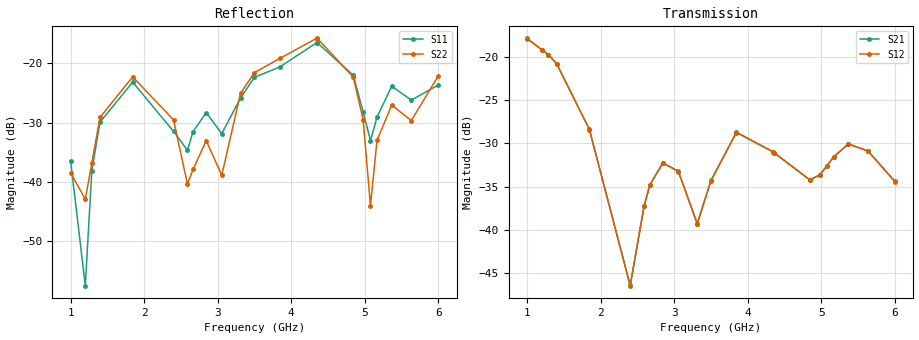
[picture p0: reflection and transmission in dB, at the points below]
!Agilent Technologies,E8364B,MY43040528,A.07.50.67
!Agilent E8364B: A.07.50.67
!Date: Sunday, March 01, 2026 16:23:47
!Correction: S11(Full 2 Port(1,2))
!S21(Full 2 Port(1,2))
!S12(Full 2 Port(1,2))
!S22(Full 2 Port(1,2))
!S2P File: Measurements: S11, S21, S12, S22:
# Hz S  dB  R 50
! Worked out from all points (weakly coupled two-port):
!   451 points, 1 GHz to 6 GHz, reference 50 ohm
!   highest |S21| = -17.88 dB at 1 GHz (marker M1); lowest = -46.4 dB at 2.4 GHz (marker M2)
!   lowest |S11| = -57.5 dB at 1.2 GHz (marker M3), VSWR 1.00, Z = 50 - j0.125 ohm
!   |S11| at or under -10 dB: start of sweep to end of sweep
!   |S22| runs from -44.0 to -15.7 dB; largest |S21 - S12| = 0.00055
!   S11 on the Smith chart (normalised r, x): 1 GHz: 1.03, +0.01; 4.356 GHz: 1.20, -0.26; 6 GHz: 0.97, -0.13
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1e9  -36.43 24.8  -17.88 27.6  -17.92 27.7  -38.46 -7.3
1.2e9  -57.52 -69.8  -19.19 -32.7  -19.23 -32.7  -42.92 77.2
1.288889e9  -38.14 -149.9  -19.75 -61.7  -19.78 -61.6  -36.85 111.4
1.4e9  -29.92 -177.1  -20.80 -99.1  -20.84 -99.0  -29.11 99.5
1.844444e9  -23.16 87.6  -28.38 119.6  -28.41 119.7  -22.27 -8.3
2.4e9  -31.46 23.9  -46.42 -118.5  -46.45 -118.4  -29.52 -113.3
2.588889e9  -34.64 71.3  -37.24 97.6  -37.27 97.7  -40.34 -101.1
2.666667e9  -31.50 77.1  -34.81 62.8  -34.84 62.8  -37.86 -63.2
2.844444e9  -28.31 56.1  -32.25 -10.1  -32.29 -10.1  -33.03 -82.9
3.055556e9  -31.85 44.5  -33.24 -89.4  -33.27 -89.4  -38.89 -67.1
3.311111e9  -25.85 76.4  -39.28 -137.4  -39.31 -137.4  -25.05 -67.1
3.5e9  -22.35 50.8  -34.27 -153.9  -34.30 -153.8  -21.55 -108.6
3.844444e9  -20.60 21.9  -28.72 85.9  -28.76 86.0  -19.16 -159.9
4.344444e9  -16.52 -43.6  -30.98 -94.8  -31.02 -94.8  -15.77 109.3
4.355556e9  -16.52 -45.4  -31.07 -98.8  -31.11 -98.7  -15.80 107.0
4.844444e9  -22.02 -125.8  -34.22 47.7  -34.26 47.8  -22.31 0.0
4.977778e9  -28.16 -135.8  -33.63 -27.4  -33.67 -27.3  -29.48 -28.4
5.077778e9  -33.04 -99.4  -32.57 -82.0  -32.60 -81.9  -44.03 13.1
5.166667e9  -29.08 -68.6  -31.55 -127.3  -31.59 -127.3  -33.01 74.6
5.366667e9  -23.85 -88.7  -30.07 139.7  -30.10 139.7  -27.04 37.1
5.633333e9  -26.19 -113.8  -30.87 29.9  -30.91 29.9  -29.64 26.1
6e9  -23.65 -100.8  -34.40 -75.0  -34.44 -74.9  -22.12 -3.4
